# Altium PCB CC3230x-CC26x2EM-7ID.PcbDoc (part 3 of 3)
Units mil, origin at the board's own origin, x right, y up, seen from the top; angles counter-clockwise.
Board outline 2700 x 2300 mil, 4 copper layers (Top Layer, GND, PWR, Bottom Layer), stack 48.84 mil thick; 158 components, 102 nets, 511 pads, 818 vias.

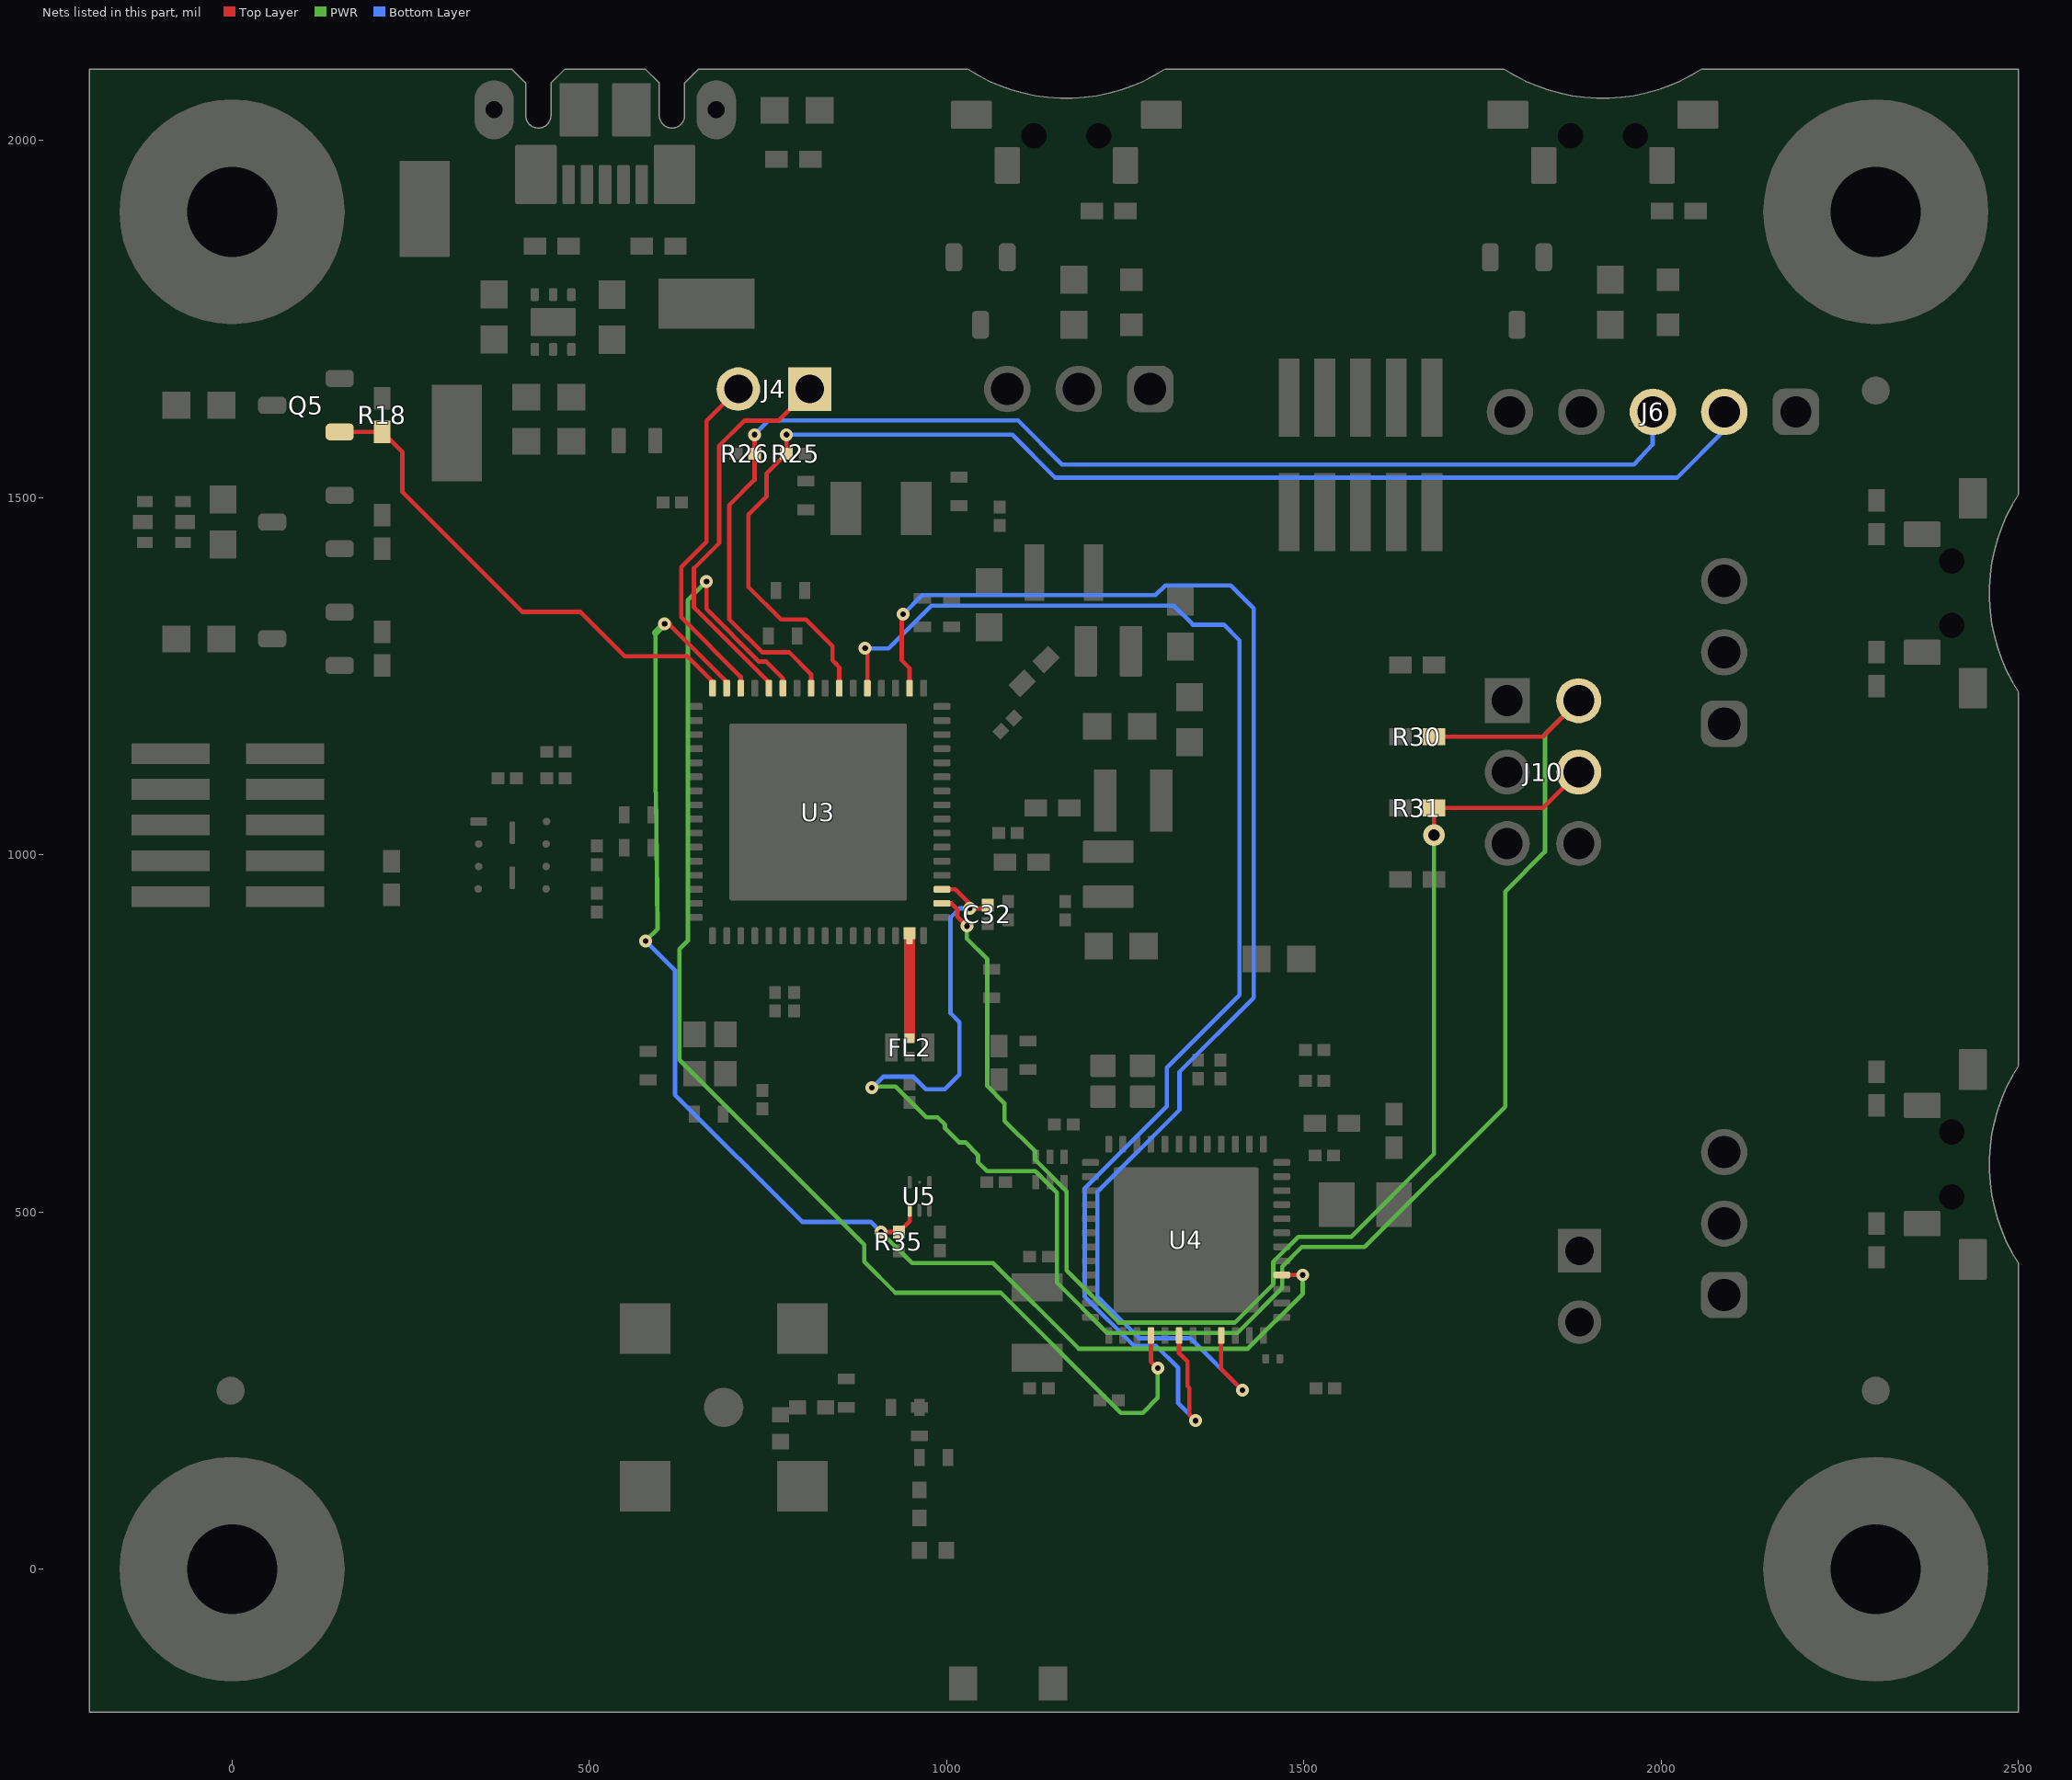
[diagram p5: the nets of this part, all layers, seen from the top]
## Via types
v1: diameter 18, hole 8, Top Layer to Bottom Layer, tented both sides, 626 vias
v2: diameter 19.68, hole 7.87, Top Layer to Bottom Layer, 55 vias
v3: diameter 20, hole 10, Top Layer to Bottom Layer, tented both sides, 48 vias
v4: diameter 24, hole 12, Top Layer to Bottom Layer, tented both sides, 37 vias
v5: diameter 20, hole 8, Top Layer to Bottom Layer, tented both sides, 24 vias
v6: diameter 30, hole 16, Top Layer to Bottom Layer, tented both sides, 23 vias
v7: diameter 20, hole 8, Top Layer to Bottom Layer, tented bottom, 4 vias
v8: diameter 18, hole 8, Top Layer to Bottom Layer, 1 vias

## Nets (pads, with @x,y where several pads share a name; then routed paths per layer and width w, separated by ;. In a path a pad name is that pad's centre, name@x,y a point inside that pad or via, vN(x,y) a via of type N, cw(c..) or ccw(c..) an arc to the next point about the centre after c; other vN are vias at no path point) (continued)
WiFi_P34_SOP1: J10.4 R31.2 U3.34 | length 1961.8
  Top Layer w6: U3.34@993.23,932.05 1006.86,932.05 1014.79,924.12 1014.79,913.82 v1(1028.23,900.39) ; v6(1681.95,1027.73) R31.2@1681.95,1065.54 1834.08,1065.54 J10.4@1884.35,1115.81
  PWR w6: v1(1028.23,900.39) 1028.23,882.53 1056.74,854.02 1056.74,676.12 1080.75,652.1 1080.75,627.61 1123.69,584.67 1123.69,573.04 1167.72,529.01 1167.72,418.32 1240.76,345.29 1402.98,345.29 1456.93,399.24 1456.93,430.29 1492.03,465.38 1565.92,465.38 1681.95,581.4 v6(1681.95,1027.73)
WiFi_P35_SOP0: C32.1 J10.2 R30.2 U3.35 | length 2578
  Top Layer w6: U3.35@993.23,951.73 1011.76,951.73 1032.4,931.09 v1(1032.4,924.92) 1052.43,924.92 C32.1@1057.24,929.73 ; R30.2@1681.95,1165.54 1834.08,1165.54 J10.2@1884.35,1215.81
  PWR w6: v1(895.34,673.98) 897.03,675.67 928.32,675.67 971.24,632.76 987.23,632.76 997.54,622.45 997.54,616.96 1016.94,597.56 1026.13,597.56 1043.73,579.95 1043.73,569.82 1056.25,557.3 1123.87,557.3 1154.11,527.07 1154.11,401.21 1224.54,330.78 1406.72,330.78 1469.59,393.65 1469.59,423.7 1496.81,450.93 1584.84,450.93 1781.5,647.59 1781.5,948.56 1837.15,1004.21 1837.15,1168.61 J10.2@1884.35,1215.81
  Bottom Layer w6: v1(895.34,673.98) 910.83,689.47 953.46,689.47 971.05,671.89 997.06,671.89 1017.74,692.57 1017.74,765.91 1005.24,778.41 1005.24,912.13 1018.04,924.92 v1(1032.4,924.92)
WiFi_P50_GPIO_00: U3.50 U4.21 | length 2029.8
  Top Layer w6: v1(938.94,1336.67) 937,1334.73 937,1272 947.95,1261.05 U3.50@947.95,1233.23 ; U4.21@1384.16,327.21 1383.97,327.02 1383.97,280.39 v1(1413.74,250.63)
  Bottom Layer w6: v1(938.94,1336.67) 965.82,1363.55 1292.15,1363.55 1305.89,1377.28 1397.38,1377.28 1429.69,1344.97 1429.69,800.12 1325.65,696.07 1325.65,642.94 1210.93,528.22 1210.93,381.57 1269.07,323.43 1340.94,323.43 v1(1413.74,250.63)
WiFi_P53_GPIO_30: U3.53 U4.18 | length 2019.1
  Top Layer w6: v1(885.72,1289.09) 888.9,1285.91 U3.53@888.9,1233.23 ; U4.18@1325.11,327.21 1325.11,302.24 1336.73,290.62 1336.73,256.44 1339.64,253.53 1339.64,216.52 v1(1348.21,207.94)
  Bottom Layer w6: v1(885.72,1289.09) 918.83,1289.09 978.32,1348.58 1317.9,1348.58 1344.37,1322.11 1387.8,1322.11 1409.7,1300.2 1409.7,803.94 1307.85,702.09 1307.85,647.73 1193.04,532.91 1193.04,381.58 1262.19,312.42 1293.21,312.42 1323.81,281.82 1323.81,232.34 v1(1348.21,207.94)
WiFi_P55_GPIO_01: J6.2 R25.1 U3.55 | length 1840.6
  Top Layer w6: v1(775.69,1588.07) R25.1@775.69,1561.54 747.73,1533.57 747.73,1501.25 722.37,1475.9 722.37,1374.83 767.92,1329.28 802.72,1329.28 840,1292 840,1272.26 845.84,1266.42 845.84,1266.16 849.53,1262.47 U3.55@849.53,1233.23
  Bottom Layer w6: v1(775.69,1588.07) 1091.6,1588.07 1151.68,1527.99 2022.13,1527.99 2088.26,1594.52 J6.2@2088.26,1619.87
  Bottom Layer w10: J6.2@2088.12,1620 J6.2@2088.26,1619.87
WiFi_P57_GPIO_02: J6.3 R26.1 U3.57 | length 1787.6
  Top Layer w6: v1(731,1588.07) R26.1@731,1561.54 731,1524.8 695.72,1489.52 695.72,1329.41 741.6,1283.53 779.37,1283.53 810.16,1252.74 U3.57@810.16,1233.23
  Bottom Layer w6: v1(731,1588.07) 750.87,1607.94 1099.84,1607.94 1161.51,1546.27 1961.68,1546.27 1987.77,1574.33 J6.3@1987.77,1619.65
  Bottom Layer w10: J6.3@1987.77,1619.65 J6.3@1988.12,1620
WiFi_P59_GPIO_04: U3.59 U4.16 | length 1873.1
  Top Layer w6: v1(663.8,1382.7) 663.8,1344.09 737.36,1270.53 747.44,1270.53 770.71,1247.26 770.79,1247.26 U3.59@770.79,1233.23 ; U4.16@1285.74,327.21 1285.74,291.09 v1(1295.3,281.53)
  PWR w6: v1(663.8,1382.7) 637.7,1356.6 637.7,879.57 626,867.87 626,713.03 884.69,454.33 884.69,430.34 927.98,387.06 1075.53,387.06 1243.67,218.92 1274.41,218.92 1295.3,239.81 v1(1295.3,281.53)
WiFi_P60_GPIO_05: J4.1 U3.60 | length 557.1
  Top Layer w6: U3.60@751.1,1233.23 751.1,1241.24 646.2,1346.13 646.2,1401.16 681.52,1436.48 681.52,1572.68 716.51,1607.68 764.07,1607.68 J4.1@808.31,1651.91
WiFi_P62_GPIO_07: J4.2 U3.62 | length 486.4
  Top Layer w6: J4.2@708.31,1651.91 663.69,1607.29 663.69,1438.27 628.24,1402.82 628.24,1332.76 711.7,1249.3 U3.62@711.73,1233.23
WiFi_P63_GPIO_08: R35.2 U3.63 U4.28 U5.4 | length 1992.4
  Top Layer w6: v8@610.22,1323.51 692.05,1241.68 U3.63@692.05,1233.23 ; v1(907.88,471.99) R35.2@933.07,471.99 948.07,486.99 U5.4@948.07,502.41 ; U4.28@1468.81,411.86 v1(1498.19,411.86)
  Top Layer w10: v8(605.27,1323.51) v8@610.22,1323.51
  PWR w6: v1(578.48,879.48) 595.41,896.41 592.94,1087.68 ; 592.47,1088.19 592.47,1310.71 ; v1(907.88,471.99) 951.46,428.4 1064.98,428.4 1184.75,308.63 1421.33,308.63 1498.19,385.49 v1(1498.19,411.86)
  PWR w10: 592.47,1310.71 v8(605.27,1323.51)
  Bottom Layer w6: v1(578.48,879.48) 619.72,838.24 619.72,664.32 797.79,486.25 893.61,486.25 v1(907.88,471.99)
WiFi_P64_GPIO_09: Q5.1 R18.1 U3.64 | length 708.5
  Top Layer w6: Q5.1@150.53,1591.9 R18.1@209.96,1591.9 238.27,1563.58 238.27,1507.94 406.21,1340 487.43,1340 549.43,1278 637.08,1278 672.33,1242.75 U3.64@672.33,1233.23
WIFI_RF: FL2.1 pad.2 U3.31 | length 146.1
  Top Layer w15: FL2.1@947.95,744.17 U3.31@947.95,886.77 947.95,890.11 pad.2@948.06,890.22
pads on no net: FID1.1 FID2.1 FID3.1 FL1.2 H2.1 H3.1 H4.1 H5.1 H6.0 H7.0 H8.0 H9.0 J1.7 J2.7 J3.2 J3.3 J3.4 Label1.0 SH-J1.0 SH-J2.0 SH-J3.0 SH-J4.0 SW1. SW2. SW3. SW4. U1.5 U1.7@431.45,1745.82 U1.7@466.88,1745.82 U3.7 U3.8 U3.15 U3.26 U3.27 U3.28 U3.29 U3.30 U3.58 U3.61 U3.65@725.51,965.51 U3.65@725.51,1012.76 U3.65@725.51,1060 U3.65@725.51,1107.24 U3.65@725.51,1154.49 U3.65@772.76,965.51 U3.65@772.76,1012.76 U3.65@772.76,1060 U3.65@772.76,1107.24 U3.65@772.76,1154.49 U3.65@820,965.51 U3.65@820,1012.76 U3.65@820,1060 U3.65@820,1107.24 U3.65@820,1154.49 U3.65@867.24,965.51 U3.65@867.24,1012.76 U3.65@867.24,1060 U3.65@867.24,1107.24 U3.65@867.24,1154.49 U3.65@914.49,965.51 U3.65@914.49,1012.76 U3.65@914.49,1060 U3.65@914.49,1107.24 U3.65@914.49,1154.49 U4.5 U4.6 U4.7 U4.8 U4.9 U4.10 U4.11 U4.12 U4.17 U4.29 U4.30 U4.31 U4.32 U4.36 U4.39 U4.40 U4.41 U4.42 U4.43

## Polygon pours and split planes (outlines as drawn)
VCC on Top Layer "VCC_L01_P000" (solid, remove dead copper, pour order 0): 437.35,1716.42 403.85,1716.42 396.45,1709.02 396.45,1697.78 376.91,1678.24 272.46,1678.24 255.62,1661.39 255.62,1514.32 286.97,1482.97 434.91,1482.97 447.34,1495.39 447.34,1680.18 441.17,1686.34 441.17,1712.6
VBUS_USB1_5V on Top Layer "VBUS_USB1_5V_L01_P006" (solid, remove dead copper, pour order 6): 211.22,1975.81 211.22,1801.61 258.54,1754.3 393.48,1754.3 410.61,1771.43 490.52,1771.43 496.41,1777.31 496.41,1827.79 493.94,1830.26 456.92,1830.26 447.2,1839.98 447.2,1873.43 437.11,1883.52 402.56,1883.52 380.06,1906.02 380.06,1953.32 328.03,2005.36 240.76,2005.36
no net on Top Layer "NONET_L01_P016" (solid, remove dead copper, pour order 16): -425.28,1755.12
GND on Top Layer "GND_L01_P024" (solid, remove dead copper, pour order 24): 1093.77,716.96 1093.77,691.55 1107.56,677.76 1158.72,677.76 1162.91,681.94 1162.91,712.87 1203,752.96 1332.75,752.96 1353.5,773.71 1353.5,798 1347.18,804.32 1181.13,804.32
GND on Top Layer "GND_L01_P010" (solid, remove dead copper, pour order 10): -200,2100 -200,-200 2500,-200 2500,2100
no net on PWR "NONET_L03_P022" (solid, remove dead copper, pour order 22): 1043.06,892.51
VDD_ANA on PWR "VDD_ANA_L03_P012" (solid, remove dead copper, pour order 12): 783.79,811.46 788.64,806.61 813.94,806.61 819.71,812.38 819.71,846.14 830.46,856.89 1138.79,856.89 1193.68,802 1254,802 1270,818 1270,896 1229,937 1086.31,936.99 1054.94,968.38 1054.94,1273.06 1033.29,1294.71 997.33,1294.71 979.21,1276.58 979.21,916.21 962.81,899.81 826.71,899.8 783.8,856.89
GND on PWR "GND_L03_P018" (solid, remove dead copper, pour order 18): -200,2100 -200,-200 2500,-200 2500,2100
VCC on PWR "VCC_L03_P014" (solid, remove dead copper, pour order 14): 1123.41,623.88 1150.52,596.78 1381.14,596.78 1464.15,513.77 1701.37,513.77 1739.31,475.82 2417.78,475.82 2499.99,558.03 2499.99,2100 782.28,2100 -177.09,2100 -177.09,773 631,773 661,803 661,1208 678,1225 959,1225 969,1235 969,1287 993.91,1311.91 1042.09,1311.91 1063,1291 1063,979.89 1095.89,947 1237,947 1281.91,902.09 1281.91,814.59 1258.36,791.04 1142.7,791.04 1101.25,749.59 1101.25,646.04
GND on GND "GND_L02_P008" (solid, remove dead copper, pour order 8): -200,2100 -200,-200 2500,-200 2500,2100
GND on Bottom Layer "GND_L04_P020" (solid, remove dead copper, pour order 20): -200,2100 -200,-200 2500,-200 2500,2100

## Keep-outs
Bottom Layer:
  circle w0: c1128.37,1209.13 r16
  circle w0: c1158.78,981.27 r16
  circle w0: c1124.35,1032.86 r16
Keep-Out Layer:
  lines w10: 2505,427.95 2505,-205 -205,-205 -205,2105 393.11,2105 415.78,2082.33 415.78,2035.04 ccw(c428.5,2035.04) 441.21,2035.04 441.21,2082.29 463.93,2105 579.99,2105 602.79,2082.2 602.79,2035.04 ccw(c615.51,2035.04) 628.22,2035.04 628.22,2082.25 650.97,2105 1028.76,2105 ccw(c1167.36,2320) 1305.95,2105 1779.55,2105 ccw(c1918.15,2319.49) 2056.74,2105 2505,2105 2505,1504.74 ccw(c2720.01,1366.14) 2504.99,1227.55 2504.99,705.13 ; 2505.14,428.04 cw(c2718.23,566.54) 2505.14,705.03
  text ".Layer_Name" at 377,-1058.49 h60

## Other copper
Top Layer:
  region net NetC46_2: 804.05,248.24 700.97,248.24 700.97,204.54 804.05,204.54
  rectangle net GND: 672,912 967.28,1207.28
  pour cut-out: 2481.02,-174.49 2500,-174.49 2500,-192.69 2476.38,-192.69 -199.99,-192.69 -199.99,-174.49
  region net NetC45_1: 961.86,488.67 959.21,488.67 954.74,474.82 968.94,474.82 964.7,488.64
  region net NetR33_1: 948.06,554.22 950.71,554.22 955.17,568.07 940.98,568.07 945.22,554.25
  pour cut-out: 1042.71,-195.7 1128.9,-195.7 1128.9,-144.2 1148.7,-144.2 1148.7,1.15 912.48,1.15 912.48,-144.2 1042.71,-144.2
  pour cut-out: 991.9,-140 929.9,-140 929.9,-1 933.9,-1 933.9,52.41 989.9,52.41 989.9,-1 991.9,-1
  region: 2338.66,652.63
  pour cut-out: 631,887.54 631.77,886.77 973.76,886.77 973.76,929.22 997.17,929.22 997.17,1228 631,1228
  pour cut-out: 1580.87,551.78 1590.87,551.78 1590.87,468.78 1580.87,468.78
  pour cut-out: 1215.43,575.87
  pour cut-out: 1217.6,580.73 1217.6,344.86 1450.76,344.86 1450.76,580.73
  pour cut-out: 786.17,714.1 816.44,744.36 816.44,1299 456,1299 450,1293 450,1163 448,1161 258,1161 253,1156 253,863 260,856 524,856 530,850 551.66,850 569.25,832.41 569.25,802.53 560.93,794.21 534.94,794.2 530,789.27 530,523.54 765.05,523.54 765.05,714.1
  pour cut-out: -173.8,1164.45 -49.44,1164.45 -33.44,1148.45 -33.44,925.98 -40.56,918.86 -166.52,918.86 -173.8,926.14
  pour cut-out: 979.35,223.62 983.85,219.12 983.85,169.03 946.53,169.03 946.53,204.09 931.78,204.09 931.78,248.53 979.35,248.53
  pour cut-out: 1067.29,767.74 1067.29,757.89 1071.86,753.32 1117.47,753.32 1119.92,755.76 1119.92,768.92 1118.34,770.49 1070.05,770.49
  pour cut-out: 1124.57,765.99 1168.42,809.84 1395.59,809.84 1412,826.25 1412,1570 747,1570 742,1565 742,1369 842,1269 979,1269 1045.28,1202.72 1045.27,765.99
  pour cut-out: 1173.51,709.44 1173.51,654.95 1214.26,614.2 1264.59,614.2 1302.5,652.11 1302.5,732.27 1296.61,738.17 1202.24,738.17
  pour cut-out: 1456.13,1525.65 1456.13,1415.1 1540.36,1415.1 1701.72,1415.1 1701.72,1525.65
  pour cut-out: 942.01,132.89 981.69,132.89 981.69,49.9 942.01,49.9
  pour cut-out: 981.69,49.9 942.01,49.9 942.01,90.79 981.69,90.79
  pour cut-out: 944.35,169.03 979.35,169.03 979.35,40.74 944.35,40.74
  pour cut-out: 584.59,263.79 584.59,266.85 574.59,266.85 574.59,265.13 573.26,263.8 ccw(c582.02,254.98) 569.58,255.02 569.58,198.84 ccw(c579.43,198.83) 572.47,191.87 572.92,191.42 ccw(c578.79,197.29) 578.79,188.99 671.2,188.99 671.2,167.43 687.94,167.43 ccw(c687.94,226.18) 729.48,184.64 813.82,186.88 813.82,266.15 732.55,266.15 731.47,266.15 729.46,268.15 ccw(c687.94,226.63) 687.93,285.35 671.2,285.36 671.2,263.79
  text "1" at 209.59,-142.38 h30
  text ".Layer_Name" at 377,-1058.49 h60
GND:
  pour cut-out: 912.48,5.35 1148.7,5.35 1148.7,-191.5 912.48,-191.5
  text "2" at 204.59,-142.38 h30
  text ".Layer_Name" at 377,-1058.49 h60
PWR:
  pour cut-out: 951.77,836.58 959.79,828.56 981.29,828.56 991.41,838.68 991.41,855.55 989.78,857.18 835.55,857.18 819.77,841.41 819.77,802.75 814.48,797.46 841.49,797.46 880.62,836.58
  pour cut-out: 979.11,854.09 979.11,848.55 1047.77,848.55 1055.5,856.28 1055.5,878.2 1042.56,891.14 1016.17,891.14
  pour cut-out: 1045.23,892.35 1073.5,892.35 1077.33,896.18 1093.36,896.18 1095.75,893.79 1095.75,876.91 1067.4,848.55 1047.77,848.55
  pour cut-out: 1186.45,794.47 1230.19,794.47 1240.13,784.53 1240.13,773.35 1232.52,765.74 1196.04,765.74 1186.46,775.32 1186.46,785.64 1190.39,789.57
  pour cut-out: 1305.95,903.92 1305.95,832.01 1314.67,823.29 1331.93,823.29 1339.94,831.3 1339.94,900.91 1329.76,911.09 1313.5,911.09
  pour cut-out: 1384.51,741.04 1384.51,726.12 1394.58,716.04 1402.37,716.04 1410.16,723.83 1410.16,745.67 1406.85,748.97
  pour cut-out: 1154.25,895.04 1154.25,880.19 1160.04,874.4 1171.42,874.4 1177.2,880.18 1177.2,893.38 1173.34,897.24 1156.45,897.24
  pour cut-out: 1644.61,651.8 1640.35,647.55 1640.35,623.5 1658.39,605.46 1669.66,605.46 1681.06,616.86 1681.06,640.91 1670.41,651.55
  pour cut-out: 1583.38,987.06 1578.96,982.64 1578.96,957.25 1590.81,945.4 1609.57,945.4 1618.28,954.11 1618.28,984.96 1616.19,987.05
  pour cut-out: 1323.35,1128.78 1332.36,1128.78 1366.22,1162.64 1366.22,1172.32 1386.9,1172.32 1395.91,1163.31 1395.91,1138.62 1382.23,1124.95 1371.39,1124.95 1363.71,1117.26 1363.71,1105.76 1357.38,1099.43 1340.7,1099.43 1324.52,1115.61 1324.52,1121.61
  pour cut-out: 956.13,1408.74 1001.58,1408.74 1008.27,1415.43 1008.27,1432.27 1003.4,1437.14 1003.4,1458.04 1009.08,1463.72 1027.35,1463.72 1032.42,1458.65 1032.42,1446.88 1053.71,1425.59 1053.71,1409.54 1043.58,1399.4 1034.04,1399.4 1023.09,1388.45 1023.09,1384.59 1015.98,1377.49 953.69,1377.49 949.63,1381.55 949.63,1402.24
  pour cut-out: 755.63,1415.54 744.29,1404.2 744.29,1392.34 752.58,1384.04 770.85,1384.04 778.61,1391.8 778.61,1409.99 773.06,1415.54
  pour cut-out: 490.75,1074.86 508.91,1093.01 508.91,1109.03 515.22,1115.34 530.2,1115.34 533.02,1112.53 533.02,1096.21 523.97,1087.16 523.97,1065.44 519.3,1060.77 504.84,1060.77
  pour cut-out: 1566.06,1733.23 1588.04,1733.23 1596.39,1724.87 1611.76,1724.87 1619.72,1732.83 1637.38,1732.83 1646.41,1723.79 1646.41,1703.98 1637.51,1695.08 1619.56,1695.08 1610.53,1704.11 1596.93,1704.11 1586.55,1693.73 1567.14,1693.73 1557.3,1703.57 1557.3,1724.47
  pour cut-out: 912.48,5.35 1148.7,5.35 1148.7,-191.5 912.48,-191.5
  pour cut-out: 1072.48,791.03 1072.48,771.31 1079.45,764.34 1107.62,764.34 1112.51,769.23 1112.51,796.81 1106.43,802.89 1084.34,802.89
  pour cut-out: 845.27,664.51 845.27,615.67 864.07,596.86 927.94,596.86 969.49,555.31 1104.01,555.31 1123.69,574.99 1123.69,584.67 1103.54,604.83 1085.8,604.83 1075.91,594.94 1051.6,594.94 1042.54,604 1042.54,620.56 1027.94,635.16 915.61,635.16 874.89,675.88 856.64,675.88
  pour cut-out: 891.95,451.18 891.95,362.82 907.77,347.01 907.77,260.92 919.87,248.81 1026.14,248.81 1049.68,272.35 1049.68,450.61 1028.41,471.89 912.66,471.89
  text "3" at 204.59,-142.38 h30
  text ".Layer_Name" at 377,-1058.49 h60
Bottom Layer:
  pour cut-out: 912.48,5.35 1148.7,5.35 1148.7,-191.5 912.48,-191.5
  pour cut-out: 1296.82,1371.08 1397.03,1371.08 1424.57,1343.54 1424.57,1310.4 1419.44,1305.26 1398.9,1325.8 1342.1,1325.8
  pour cut-out: 953.54,510.78 963.31,501 968.45,501 968.45,523.77 967.09,525.14 946.81,545.41 907.08,545.41 875.02,513.35 875.02,497.68 885.66,487.04 897.75,487.04 911.92,488 911.92,502.76 919.93,510.78
  text "4" at 224.58,-142.38 h30
  text ".Layer_Name" at 377,-1058.49 h60

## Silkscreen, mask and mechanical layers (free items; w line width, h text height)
Top Overlay:
  lines w6: 393.52,1823.43 402.82,1823.43 418.3,1807.95 ; 756.49,827.14 756.49,834.76 769.91,848.17 ; 965.82,1375.41 965.82,1386.91 971.57,1392.66
  lines w10: -88.74,1401.47 -54.66,1372.13 ; -55.89,1372.14 242.7,1372.14
  text "WI-FI RESET" at 835.79,1882.16 h30
  text "BT RESET" at 1683.28,1881.32 h30
  text "5V" at 236.92,1741.43 h30
  text "GND" at 759.15,1739.16 h30
  text "BT RESET MUX" at 1023.01,1565.85 h30
  text "TX" at 2108.82,1508.6 h30 r90
  text "RX" at 2006.06,1507.65 h30 r90
  text "VCC" at 2203.77,1482.84 h30 r90
  text "GND" at 1802.94,1476.08 h30 r90
  text "VCC" at 276.09,1470.11 h30
  text "GREEN -> P64" at 260.64,1416.17 h30
  text "nRESET" at 1902.38,1390.77 h30 r90
  text "BT" at 2153.66,1369.25 h30
  text "RED   -> P01" at 262.88,1360.22 h30
  text "BT JTAG IN" at 1443.17,1338.53 h30
  text "BLUE  -> P02" at 258.4,1303.14 h30
  text "0" at 1953.72,1195.25 h40
  text "SW2 MUX" at 2029.86,1179.04 h30 r90
  text "WI-FI" at 2153.99,1164.25 h30
  text "1" at 1962.08,1090.32 h40
  text "2" at 1953.73,992.7 h40
  text "SOP" at 1794.89,912.61 h40
  text "WI-FI JTAG IN" at -160.53,855.59 h30
  text "BT" at 2155.75,568.78 h30
  text "DIO 9" at 1672.07,428.09 h30
  text "SW1 MUX" at 2016.65,384.83 h30 r90
  text "WI-FI" at 2150.52,367.26 h30
  text "DIO 8" at 1671.49,329.31 h30
  text "WIFI-2.4GHZ + BLE COEX DESIGN" at 1220.48,157.46 h30
  text "CC3230x-CC26x2EM-7ID" at 1218.84,109.34 h30
  text "REV A" at 1222.11,55.52 h30
  text ".Layer_Name" at 377,-1058.49 h60
Bottom Overlay:
  text "MAC lOG" at 821.18,1921.26 h30 r90
  text "NWP lOG" at 726.56,1917.19 h30 r90
  text "SW3" at 1098.27,1788.74 h30 r90
  text "SW4" at 1299.88,1785.96 h30 r90
Top Paste:
  text ".Layer_Name" at 377,-1058.49 h60
Top Solder:
  text ".Layer_Name" at 377,-1058.49 h60
  text ".Layer_Name" at 377,-1058.49 h60
Bottom Solder:
  text ".Layer_Name" at 377,-1058.49 h60
Drill Guide:
  text ".Layer_Name" at 377,-1058.49 h60
M1 Board Outline:
  the board outline again, w10
  text ".Layer_Name" at 377,-1058.49 h60
M2 Board Dimensions:
  rectangle: -200,-475 -75,-350
  rectangle: -75,-600 300,-475
  lines w7: -200,-475 800,-475 ; -75,-600 -75,-350 ; 50,-600 50,-350 ; 300,-600 300,-350 ; 550,-600 550,-350 ; -200,-600 800,-600 800,-350 -200,-350 -200,-600
  text "2 PLACES" at 667.62,2331.3 h30
  text "4 PLACES" at 1445.08,2282.58 h60
  text ".Layer_Name" at 377,-1058.49 h60
M3 3D STEP Top:
  text ".Layer_Name" at 377,-1058.49 h60
M4 3D STEP Bottom:
  text ".Layer_Name" at 377,-1058.49 h60
M5 Assembly Top:
  lines w10: -492,-1130.17 6108,-1130.17 ; -492,-926.83 6110,-926.83 ; -492,-723.5 -492,-1333.5 3513,-1333.5 6110,-1333.5 6110,-723.5 -491.5,-723.5 -491.5,-1333.5 1084,-1333.5 ; 1973,-1333.5 1973,-723.5 ; 3240,-926.83 3240,-723.5 ; 4080,-926.83 4080,-723.5 ; 4702,-1340 4702,-1137.17
  text "COMPONENTS MARKED 'DNP' SHOULD NOT BE POPULATED." at 953.5,-518.5 h60
  text "ASSEMBLY VARIANT:" at 953,-634 h60
  text ".VariantName" at 1989,-634 h60
  text "PCB VIEWED FROM TOP SIDE" at -428.5,-855.67 h60
  text "BOARD #:" at 2048,-855.67 h60
  text ".PRJ_Number" at 2593.5,-855.67 h60
  text "REV:" at 3438,-855.67 h60
  text ".PCB_Rev" at 3729.5,-855.67 h60
  text "SVN REV:" at 4276,-855.67 h60
  text ".VersionControl_RevNumber" at 4782,-855.67 h60
  text "PROJECT TITLE:" at 2048,-1059 h60
  text ".PRJ_Title" at 2883.92,-1067.67 h60
  text "PLOT NAME =" at -428.5,-1264.34 h60
  text ".plot_File_Name" at 377,-1264.34 h60
  text "GENERATED    :" at 2050,-1264.34 h60
  text ".Print_Date" at 2919.5,-1264.34 h60
  text ".Print_Time" at 3648.5,-1264.34 h60
  text "TEXAS INSTRUMENTS" at 4913,-1264.34 h60
M6 Assembly Bottom:
  lines w10: -492.5,-927.33 6109.5,-927.33 ; -490.5,-1130.67 6109.5,-1130.67 ; 915.5,-1340.5 915.5,-1137.67 ; 1537.5,-927.33 1537.5,-724 ; 2377.5,-927.33 2377.5,-724 ; 3644.5,-1334 3644.5,-724 ; 4533.5,-1334 6109,-1334 6109,-724 -492.5,-724 -492.5,-1334 2104.5,-1334 6109.5,-1334 6109.5,-724
  text "COMPONENTS MARKED 'DNP' SHOULD NOT BE POPULATED." at 5902,-518 h60
  text ".VariantName" at 4858,-634 h60
  text "ASSEMBLY VARIANT:" at 5897,-634 h60
  text ".VersionControl_RevNumber" at 835.5,-856.17 h60
  text "SVN REV:" at 1341.5,-856.17 h60
  text ".PCB_Rev" at 1888,-856.17 h60
  text "REV:" at 2179.5,-856.17 h60
  text ".PRJ_Number" at 3024,-856.17 h60
  text "BOARD #:" at 3569.5,-856.17 h60
  text "PCB VIEWED FROM BOTTOM SIDE" at 6046,-856.17 h60
  text ".TID" at 3024,-1059.5 h60
  text "TID #:" at 3569.5,-1059.5 h60
  text "TEXAS INSTRUMENTS" at 704.5,-1264.84 h60
  text ".Print_Time" at 1969,-1264.84 h60
  text ".Print_Date" at 2698,-1264.84 h60
  text "GENERATED    :" at 3567.5,-1264.84 h60
  text ".plot_File_Name" at 5240.5,-1264.84 h60
  text "PLOT NAME =" at 6046,-1264.84 h60
M9 Title Sheet:
  drawing of 57 lines, arcs and shapes, not listed
  text "1" at 539.84,7836.5 h70
  text "2" at 3035.5,7836.5 h70
  text "3" at 5524.84,7836.5 h70
  text "4" at 8031.51,7836.5 h70
  text "5" at 10530.5,7836.5 h70
  text "6" at 13035.5,7836.5 h70
  text "A" at -616.5,6693.5 h70
  text "A" at 14183.5,6693.5 h70
  text "B" at -616.5,4313.5 h70
  text "B" at 14183.5,4313.5 h70
  text "C" at -616.5,1938.5 h70
  text "C" at 14183.5,1938.5 h70
  text "PROJECT TITLE:" at 11143.5,77.5 h45
  text ".PRJ_Title" at 11193.5,-55.83 h70
  text "DESIGNED FOR:" at 11143.5,-223.5 h45
  text ".PRJ_Customer" at 11193.5,-363.5 h70
  text "D" at -616.5,-431.5 h70
  text "D" at 14183.5,-431.5 h70
  text "FILE NAME:" at 11143.5,-523.5 h45
  text ".PCB_File_Name_No_Path" at 11193.5,-643.5 h70
  text "Texas Instruments (TI) and/or its licensors do not warrant the accuracy or completeness of this specification" at 6174,-805.34 h45
  text "ENGINEER:" at 11143.5,-813.5 h45
  text "LAYOUT BY:" at 12648.5,-813.5 h45
  text "or any information contained therein. TI and/or its licensors do not warrant that this design will meet" at 6129.01,-918 h45
  text ".PRJ_Engineer" at 11193.5,-968.49 h70
  text ".PCB_Layout" at 12699,-968.49 h70
  text "the specifications, will be suitable for your application or fit for any particular purpose, or will operate in" at 6129.01,-1030.67 h45
  text ".Layer_Name" at 377,-1058.49 h60
  text "ALTIUM DESIGNER VERSION:" at 12648.5,-1123.5 h45
  text "an implementation. TI and/or its licensors do not warrant that the design is production worthy. You should" at 6129.01,-1143.33 h45
  text "completely validate and test your design implementation to confirm the system functionality for your application." at 6174,-1256 h45
  text ".print_Scale" at 11193.5,-1256.83 h70
  text ".Application_BuildNumber" at 12699,-1256.83 h70
  text "1" at 539.84,-1463.5 h70
  text "2" at 3035.5,-1463.5 h70
  text "3" at 5524.84,-1463.5 h70
  text "4" at 8031.51,-1463.5 h70
  text "5" at 10530.5,-1463.5 h70
  text "WO # : 308462-8460-D" at 13035.5,-1463.5 h70
M10 Fab Notes:
  drawing of 173 lines, arcs and shapes, not listed
  text "DESIGN INFORMATION" at 12177.02,6001 h60
  text "MIN. TRACK WIDTH:" at 11532.46,5821 h60
  text "6" at 12628.7,5821 h60
  text "MIL" at 12783.46,5821 h60
  text "MIN. CLEARANCE:" at 11532.46,5689 h60
  text "3.9" at 12568.7,5689 h60
  text "MIL" at 12783.46,5689 h60
  text "19.7" at 12550.24,5557.76 h60
  text "MIN. VIA PAD SIZE:" at 11532.46,5557 h60
  text "MIL" at 12783.46,5557 h60
  text "0.05mm (2MIL)" at 12227.46,5415.29 h60
  text "MINIMUM ANNULAR RING" at 11203.23,5411 h60
  text "EXTERNAL" at 12935.46,5411 h60
  text "PER" at 11403.23,5293 h60
  text "IPC-D-275 CLASS 2 LEVEL C" at 11623.23,5293 h60
  text "MIL, HOLES" at 13111.46,5180.71 h60
  text "+/-" at 12719,5180 h60
  text "+/-" at 13573,5180 h60
  text "REGISTRATION TOLERANCES:" at 11203.23,5175 h60
  text "METAL" at 12403,5175 h60
  text "5" at 12979.2,5175 h60
  text "3" at 13812.2,5175 h60
  text "MIL" at 13928.46,5175 h60
  text "+/-" at 13573,5062 h60
  text "HOLE SIZE TOLERANCE (UNLESS OTHERWISE SPECIFIED):" at 11203.23,5057 h60
  text "3" at 13812.2,5057 h60
  text "MIL" at 13928.46,5057 h60
  text "MATERIAL:" at 11128.46,4847.54 h60
  text "FR-4 High Tg" at 12114.9,4707.21 h60
  text "FR-408" at 11549.46,4698.64 h60
  text "OTHER" at 13037.46,4698.64 h60
  text "X" at 11960,4695 h60
  text "62 MIL (1.6mm) +/-10%" at 11869.56,4535.92 h60
  text "THICKNESS:" at 11203.23,4531.64 h60
  text "X" at 11741.4,4531.64 h60
  text "OTHER" at 13154.46,4531.64 h60
  text "TOLERANCE:" at 11203.23,4373.64 h60
  text "X" at 12042.53,4373.64 h60
  text "ANSI IPC-6012 TYPE 3 CLASS 2" at 12229.48,4373.64 h60
  text "OTHER +/-" at 12229.46,4217.64 h60
  text "BOW & TWIST:" at 11203.23,4060.64 h60
  text "X" at 12042.53,4060.64 h60
  text "ANSI IPC-6012 TYPE 3 CLASS 2" at 12229.48,4060.64 h60
  text "OTHER +/-" at 12229.46,3902.13 h60
  text "DRILLING:" at 11128.46,3763.64 h60
  text "REFERENCE:" at 11203.23,3646.64 h60
  text "X" at 11851.46,3646.64 h60
  text "AS SHOWN" at 12038.46,3646.64 h60
  text "X" at 12752.46,3646.64 h60
  text "NC_DRILL FILES" at 12889.46,3646.64 h60
  text "PTH COPPER THICKNESS:" at 11203.23,3488.64 h60
  text "X" at 12333.46,3488.64 h60
  text "20-30 um" at 12470.46,3488.64 h60
  text "OTHER" at 13187.46,3488.64 h60
  text "BOARD FINISH:" at 11128.46,3329.64 h60
  text "SILKSCREEN:" at 11283.68,3211.64 h60
  text "X" at 12232.46,3211.64 h60
  text "TOP" at 12358.46,3211.64 h60
  text "BOTTOM" at 12869.46,3211.64 h60
  text "SILKSCREEN COLOR:" at 11283.68,3044.64 h60
  text "X" at 12231.42,3044.64 h60
  text "WHITE" at 12358.46,3044.64 h60
  text "OTHER" at 12869.46,3044.64 h60
  text "X" at 12953.44,2886.7 h60
  text "GREEN" at 12489.46,2885.44 h60
  text "OTHER" at 13107.46,2885.44 h60
  text "RED" at 13471.33,2879.07 h60
  text "SOLDER RESIST COLOR:" at 11283.68,2874.64 h60
  text "X" at 12952.14,2715.98 h60
  text "MATTE" at 12489.46,2715.44 h60
  text "SEMI-GLOSS" at 13107,2714.8 h60
  text "IMMERSION GOLD (ENIG)" at 12189.46,2526.92 h60
  text "ENEPIG" at 13527,2523.64 h60
  text "SURFACE FINISH:" at 11128.46,2522.64 h60
  text "X" at 12002.51,2522.64 h60
  text "IMM. TIN/SILVER OR EQUIV" at 11458,2365.64 h60
  text "OTHER" at 12889.46,2365.64 h60
  text "ARRAY/PANEL:" at 11128.46,2186.64 h60
  text "CUT AND TRIM PER M1 BOARD OUTLINE" at 12189.46,2182.35 h60
  text "N.C. ROUTE" at 12189.46,2030.64 h60
  text "X" at 12868.46,2030.64 h60
  text "V. SCORE" at 13055.46,2030.64 h60
  text "CERTIFICATION:" at 11128.46,1893.64 h60
  text "MATERIALS AND WORKMANSHIP FOR ALL PCBS" at 11853.46,1893.64 h60
  text "TO MEET OR EXCEED THE REQUIREMENTS OF:" at 11853.46,1795.64 h60
  text "X" at 11479.96,1659.13 h60
  text "ANSI IPC-A-600F CLASS ->" at 11618.96,1659.13 h60
  text "X" at 13258.02,1659.13 h60
  text "2" at 13376.96,1659.14 h60
  text "1" at 13061.96,1657.64 h60
  text "3" at 13730.96,1657.64 h60
  text "X" at 12294.02,1499.64 h60
  text "RoHS" at 12430.96,1499.64 h60
  text "OTHER" at 13075.36,1499.64 h60
  text "PER ORDER" at 13472.42,1499.64 h60
  text "ALL BOARDS MUST MEET OR EXCEED UL94-V0 REQUIREMENTS." at 11156,1334 h60
  text "PCB MUST BEAR THE UL94V-0 UL REGISTERED MATERIAL ID NUMBER" at 11156,1214 h60
  text "ADDITIONAL REQUIREMENTS:" at 11128.46,1040.64 h60
  text "MICROSECTION:" at 11203.23,925.64 h60
  text "YES" at 12108.96,925.64 h60
  text "REQUIRED" at 12970.46,769.49 h60
  text "BARE BOARD ELEC. TEST:" at 11203.23,766.64 h60
  text "NONE" at 12508.96,766.64 h60
  text "X" at 12843.46,766.64 h60
  text "PER ORDER" at 13562.46,766.64 h60
  text ".Layer_Name" at 377,-1058.49 h60
M11 Gerber Information:
  lines w10: -492,-1130.17 6108,-1130.17 ; -492,-926.83 6110,-926.83 ; -492,-723.5 -492,-1333.5 3513,-1333.5 6110,-1333.5 6110,-723.5 -491.5,-723.5 -491.5,-1333.5 1084,-1333.5 ; 1973,-1333.5 1973,-723.5 ; 3793.76,-926.83 3793.76,-723.5 ; 4236.17,-926.32 4236.17,-722.99 ; 4702,-1340 4702,-1137.17
  text "REV:" at 3822.43,-855.33 h60
  text ".PCB_Rev" at 4113.93,-855.33 h60
  text "ALL ARTWORK VIEWED FROM TOP SIDE" at -428.5,-855.67 h60
  text "BOARD #:" at 2048,-855.67 h60
  text ".PRJ_Number" at 2593.5,-855.67 h60
  text "SVN REV:" at 4276,-855.67 h60
  text ".VersionControl_RevNumber" at 4782,-855.67 h60
  text "LAYER NAME =" at -428.5,-1058.49 h60
  text "Project Title:" at 2048,-1059 h60
  text ".PRJ_Title" at 2851.52,-1071.96 h60
  text "PLOT NAME =" at -428.5,-1264.34 h60
  text ".plot_File_Name" at 377,-1264.34 h60
  text "GENERATED    :" at 2050,-1264.34 h60
  text ".Print_Date" at 2919.5,-1264.34 h60
  text ".Print_Time" at 3648.5,-1264.34 h60
  text "TEXAS INSTRUMENTS" at 4913,-1264.34 h60
M12 Stackup:
  drawing of 280 lines, arcs and shapes, not listed
  text "THIS IS AN IMPEDANCE CONTROLLED BOARD" at 4545.56,5832.14 h125
  text "NOTE : EXTERNAL LAYER CU THICKNESS ARE FINISHED THICKNESS AFTER PLATING." at 4307.96,5610.38 h75
  text "IMPEDANCE TABLE" at 5514.44,5343.65 h125
  text "LAYER NO" at 4315.05,5016.28 h70
  text "CONDUCTOR WIDTH" at 4960.56,5016.28 h70
  text "SPACING" at 6038.38,5016.28 h70
  text "IMPEDANCE +/-10%" at 6625.63,5016.28 h70
  text "REFERENCE GND" at 7806.67,5016.28 h70
  text "15 MIL" at 5247.93,4747.42 h70
  text "1" at 4424.59,4744.95 h70
  text "(TOP)" at 4524.59,4744.95 h70
  text "GND" at 8055.89,4744.95 h70
  text "50ohm" at 6873.14,4741.69 h70
  text "10 MIL" at 6089.83,4738.04 h70
  text "LAYER STACKUP" at 5290.24,1249.17 h125
  text "Layer" at 4034.23,1007.93 h60
  text "Name" at 4444.14,1007.93 h60
  text "Material" at 5303.91,1007.93 h60
  text "Thickness" at 6163.68,1007.93 h60
  text "Constant" at 6813.51,1007.93 h60
  text "Board Layer Stack" at 7383.38,1007.93 h60
  text "1" at 4034.23,887.93 h60
  text "Top Overlay" at 4444.14,887.93 h60
  text "2" at 4034.23,767.93 h60
  text "Top Solder" at 4444.14,767.93 h60
  text "Solder Resist" at 5303.91,767.93 h60
  text "0.80mil" at 6163.68,767.93 h60
  text "4.1" at 6813.51,767.93 h60
  text "3" at 4034.23,647.93 h60
  text "Top Layer" at 4444.14,647.93 h60
  text "Copper" at 5303.91,647.93 h60
  text "1.69mil" at 6163.68,647.93 h60
  text "4" at 4034.23,527.93 h60
  text "Dielectric1" at 4444.14,527.93 h60
  text "FR-4 High Tg" at 5303.91,527.93 h60
  text "9.30mil" at 6163.68,527.93 h60
  text "3.9" at 6813.51,527.93 h60
  text "5" at 4034.23,407.93 h60
  text "GND" at 4444.14,407.93 h60
  text "Copper" at 5303.91,407.93 h60
  text "1.42mil" at 6163.68,407.93 h60
  text "6" at 4034.23,287.93 h60
  text "Dielectric2" at 4444.14,287.93 h60
  text "FR-4 High Tg" at 5303.91,287.93 h60
  text "24.02mil" at 6163.68,287.93 h60
  text "4.24" at 6813.51,287.93 h60
  text "7" at 4034.23,167.93 h60
  text "PWR" at 4444.14,167.93 h60
  text "Copper" at 5303.91,167.93 h60
  text "1.42mil" at 6163.68,167.93 h60
  text "8" at 4034.23,47.93 h60
  text "Dielectric3" at 4444.14,47.93 h60
  text "FR-4 High Tg" at 5303.91,47.93 h60
  text "9.30mil" at 6163.68,47.93 h60
  text "3.9" at 6813.51,47.93 h60
  text "9" at 4034.23,-72.07 h60
  text "Bottom Layer" at 4444.14,-72.07 h60
  text "Copper" at 5303.91,-72.07 h60
  text "1.69mil" at 6163.68,-72.07 h60
  text "10" at 4034.23,-192.07 h60
  text "Bottom Solder" at 4444.14,-192.07 h60
  text "Solder Resist" at 5303.91,-192.07 h60
  text "0.80mil" at 6163.68,-192.07 h60
  text "4.1" at 6813.51,-192.07 h60
  text ".Layer_Name" at 377,-1058.49 h60
M13 Component Bodies Top:
  text ".Layer_Name" at 377,-1058.49 h60
M14 Component Bodies Bottom:
  text ".Layer_Name" at 377,-1058.49 h60
M15 Courtyards Top:
  text ".Layer_Name" at 377,-1058.49 h60
M16 Courtyards Bottom:
  text ".Layer_Name" at 377,-1058.49 h60
Drill Drawing:
  circle w10: c4605.1,2801.37 r13.28
  circle w10: c4605.1,2801.37 r22.14
  circle w10: c4605.1,2303.26 r22.14
  lines w10: 4582.96,2181.5 4627.24,2181.5 4627.24,2225.78 4582.96,2225.78 4582.96,2181.5 ; 4582.96,2391.82 4594.03,2391.82 4605.1,2380.75 4616.17,2391.82 4627.24,2391.82 4616.17,2402.89 4627.24,2413.95 4616.17,2413.95 4605.1,2425.02 4594.03,2413.95 4582.96,2413.95 4594.03,2402.89 4582.96,2391.82 ; 4582.96,2480.37 4582.96,2491.44 4594.03,2502.51 4582.96,2513.58 4582.96,2524.65 4594.03,2524.65 4605.1,2513.58 4616.17,2524.65 4627.24,2524.65 4627.24,2513.58 4616.17,2502.51 4627.24,2491.44 4627.24,2480.37 4616.17,2480.37 4605.1,2491.44 4594.03,2480.37 4582.96,2480.37 ; 4582.96,2602.13 4605.1,2579.99 4627.24,2602.13 4605.1,2624.27 4582.96,2602.13 ; 4582.96,2723.89 4627.24,2723.89 4605.1,2679.61 4582.96,2723.89 ; 4582.96,2923.14 4627.24,2923.14 4605.1,2878.86 4582.96,2923.14 ; 4582.96,2989.55 4594.03,2989.55 4605.1,2978.48 4616.17,2989.55 4627.24,2989.55 4616.17,3000.62 4627.24,3011.69 4616.17,3011.69 4605.1,3022.76 4594.03,3011.69 4582.96,3011.69 4594.03,3000.62 4582.96,2989.55 ; 4582.96,3078.1 4605.1,3089.17 4627.24,3078.1 4616.17,3100.24 4627.24,3122.38 4605.1,3111.31 4582.96,3122.38 4594.03,3100.24 4582.96,3078.1 ; 4582.96,3177.73 4627.24,3177.73 4627.24,3222 4582.96,3222 4582.96,3177.73 ; 4582.96,3288.42 4594.03,3288.42 4594.03,3277.35 4616.17,3277.35 4616.17,3288.42 4627.24,3288.42 4627.24,3310.56 4616.17,3310.56 4616.17,3321.63 4594.03,3321.63 4594.03,3310.56 4582.96,3310.56 4582.96,3288.42 ; 4582.96,3376.97 4605.1,3388.04 4627.24,3376.97 4616.17,3399.11 4627.24,3421.25 4605.1,3410.18 4582.96,3421.25 4594.03,3399.11 4582.96,3376.97 ; 4591.82,2914.28 4618.38,2914.28 4605.1,2887.71 4591.82,2914.28 ; 4591.82,2993.98 4598.46,2993.98 4605.1,2987.34 4611.74,2993.98 4618.38,2993.98 4611.74,3000.62 4618.38,3007.26 4611.74,3007.26 4605.1,3013.9 4598.46,3007.26 4591.82,3007.26 4598.46,3000.62 4591.82,2993.98 ; 4591.82,3086.96 4605.1,3093.6 4618.38,3086.96 4611.74,3100.24 4618.38,3113.52 4605.1,3106.88 4591.82,3113.52 4598.46,3100.24 4591.82,3086.96 ; 4591.82,3186.58 4618.38,3186.58 4618.38,3213.15 4591.82,3213.15 4591.82,3186.58
  lines w12: 4542.2,2151.62 7655.14,2151.62 ; 4542.2,3446.71 7655.14,3446.71 ; 4857.84,2051.99 4857.84,3546.33 ; 5175.02,2051.99 5175.02,3546.33 ; 5796.76,2051.99 5796.76,3546.33 ; 6041.08,2051.99 6041.08,3546.33 ; 6401.42,2051.99 6401.42,3546.33 ; 7110.94,2051.99 7110.94,3546.33 ; 4542.2,2051.99 7655.14,2051.99 7655.14,3546.33 4542.2,3546.33 4542.2,2051.99
  text "Symbol" at 4601.98,3476.59 h72
  text "Quantity" at 4887.72,3476.59 h72
  text "Finished Hole Size" at 5204.9,3476.59 h72
  text "Plated" at 5826.65,3476.59 h72
  text "Hole Type" at 6070.97,3476.59 h72
  text "Drill Layer Pair" at 6431.31,3476.59 h72
  text "Hole Tolerance" at 7140.82,3476.59 h72
  text "8" at 4887.72,3376.97 h60
  text "35.43mil (0.900mm)" at 5204.9,3376.97 h60
  text "NPTH" at 5826.65,3376.97 h60
  text "Round" at 6070.97,3376.97 h60
  text "Top Layer - Bottom Layer" at 6431.31,3376.97 h60
  text "55" at 4887.72,3277.35 h60
  text "7.87mil (0.200mm)" at 5204.9,3277.35 h60
  text "PTH" at 5826.65,3277.35 h60
  text "Round" at 6070.97,3277.35 h60
  text "Top Layer - Bottom Layer" at 6431.31,3277.35 h60
  text "179" at 4887.72,3177.73 h60
  text "8.00mil (0.203mm)" at 5204.9,3177.73 h60
  text "PTH" at 5826.65,3177.73 h60
  text "Round" at 6070.97,3177.73 h60
  text "Top Layer - Bottom Layer" at 6431.31,3177.73 h60
  text "+0.00mil/-4.00mil" at 7140.82,3177.73 h60
  text "476" at 4887.72,3078.1 h60
  text "8.00mil (0.203mm)" at 5204.9,3078.1 h60
  text "PTH" at 5826.65,3078.1 h60
  text "Round" at 6070.97,3078.1 h60
  text "Top Layer - Bottom Layer" at 6431.31,3078.1 h60
  text "48" at 4887.72,2978.48 h60
  text "10.00mil (0.254mm)" at 5204.9,2978.48 h60
  text "PTH" at 5826.65,2978.48 h60
  text "Round" at 6070.97,2978.48 h60
  text "Top Layer - Bottom Layer" at 6431.31,2978.48 h60
  text "+0.00mil/-4.00mil" at 7140.82,2978.48 h60
  text "37" at 4887.72,2878.86 h60
  text "12.00mil (0.305mm)" at 5204.9,2878.86 h60
  text "PTH" at 5826.65,2878.86 h60
  text "Round" at 6070.97,2878.86 h60
  text "Top Layer - Bottom Layer" at 6431.31,2878.86 h60
  text "+0.00mil/-4.00mil" at 7140.82,2878.86 h60
  text "23" at 4887.72,2779.24 h60
  text "16.00mil (0.406mm)" at 5204.9,2779.24 h60
  text "PTH" at 5826.65,2779.24 h60
  text "Round" at 6070.97,2779.24 h60
  text "Top Layer - Bottom Layer" at 6431.31,2779.24 h60
  text "+0.00mil/-4.00mil" at 7140.82,2779.24 h60
  text "4" at 4887.72,2679.61 h60
  text "40.00mil (1.016mm)" at 5204.9,2679.61 h60
  text "PTH" at 5826.65,2679.61 h60
  text "Round" at 6070.97,2679.61 h60
  text "Top Layer - Bottom Layer" at 6431.31,2679.61 h60
  text "6" at 4887.72,2579.99 h60
  text "43.31mil (1.100mm)" at 5204.9,2579.99 h60
  text "PTH" at 5826.65,2579.99 h60
  text "Round" at 6070.97,2579.99 h60
  text "Top Layer - Bottom Layer" at 6431.31,2579.99 h60
  text "5" at 4887.72,2480.37 h60
  text "43.31mil (1.100mm)" at 5204.9,2480.37 h60
  text "PTH" at 5826.65,2480.37 h60
  text "Round" at 6070.97,2480.37 h60
  text "Top Layer - Bottom Layer" at 6431.31,2480.37 h60
  text "+/-1.97mil" at 7140.82,2480.37 h60
  text "9" at 4887.72,2380.75 h60
  text "45.28mil (1.150mm)" at 5204.9,2380.75 h60
  text "PTH" at 5826.65,2380.75 h60
  text "Round" at 6070.97,2380.75 h60
  text "Top Layer - Bottom Layer" at 6431.31,2380.75 h60
  text "4" at 4887.72,2281.12 h60
  text "125.98mil (3.200mm)" at 5204.9,2281.12 h60
  text "PTH" at 5826.65,2281.12 h60
  text "Round" at 6070.97,2281.12 h60
  text "Top Layer - Bottom Layer" at 6431.31,2281.12 h60
  text "2" at 4887.72,2181.5 h60
  text "23.62mil (0.600mm)" at 5204.9,2181.5 h60
  text "PTH" at 5826.65,2181.5 h60
  text "Slot" at 6070.97,2181.5 h60
  text "Top Layer - Bottom Layer" at 6431.31,2181.5 h60
  text "856 Total" at 4887.72,2081.88 h60
  text "Slot definitions :" at 4601.98,2002.26 h60
  text "Routed Path Length" at 5045.28,2002.26 h60
  text "= Calculated from tool start centre position to tool end centre position." at 5577.61,2002.26 h60
  text "Hole Length" at 5045.28,1952.54 h60
  text "= Routed Path Length + Tool Size = Slot length as defined in the PCB layout" at 5377.81,1952.54 h60
  text ".Layer_Name" at 377,-1058.49 h60
M17 Embedded Cavity:
  lines w1: 482.42,320 482.42,1536.97 1545.41,1536.97 1545.41,320 482.42,320
  text "TEXAS INSTRUMENTS" at -517.73,-1455.33 h2.95
  text "LAUNCHXL-CC26X2R1" at -500.7,-1460.27 h1.22
  text "L1" at -514.61,-1462.83 h2.95
  text "WCS037 Rev. B" at -500.59,-1463.41 h1.22
  text "DATE: 2018-07-10" at -517.65,-1470.75 h2.95
  text "TEXAS INSTRUMENTS" at -882.49,-1726.92 h0.07
  text "DATE: 2018-07-10" at -882.49,-1727.31 h0.07
  text "L1" at -882.41,-1727.11 h0.07
  text "LAUNCHXL-CC26X2R1" at -882.06,-1727.05 h0.03
  text "WCS037 Rev. B" at -882.06,-1727.13 h0.03

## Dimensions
2507.67,428.31 to 2513.75,-199.53 on M2 Board Dimensions
2513.15,705.38 to 2632.17,-199.6 on M2 Board Dimensions
1918.15,2319.49 to 1949.67,2240.8 on M2 Board Dimensions
615.16,2098.33 to 640.66,2217.52 on M2 Board Dimensions
632.01,2091.2 to -201.2,2158.71 on M2 Board Dimensions
445,2133.83 to -201.03,2132.95 on M2 Board Dimensions
-200,-600 to 800,-600 on M2 Board Dimensions
-6.35,-5.64 to -308.63,-281.36 on M2 Board Dimensions
0,0 to -200,2100 on M2 Board Dimensions
-200,-200 to 0,0 on M2 Board Dimensions
0,0 to 2500,-200 on M2 Board Dimensions
-200,-200 to 0,0 on M2 Board Dimensions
